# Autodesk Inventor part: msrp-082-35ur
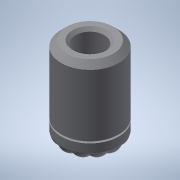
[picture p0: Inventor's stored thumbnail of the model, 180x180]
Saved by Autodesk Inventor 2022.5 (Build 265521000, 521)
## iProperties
Created: 2017-08
Part Number: msrp-082-35ur
Material: 一般
Document SubType Name: Modeling
Designer: imaocorp
Density: 1 g/cm^3
Appearance: 既定
Author: imaocorp
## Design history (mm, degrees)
node "msrp-082-35ur.x_t1"
node "msrp-082-35ur"
node "Base1"
